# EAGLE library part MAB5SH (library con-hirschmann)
Female CONNECTOR 5 pins 90 deg. with shield, horizontal (DIN 41524)

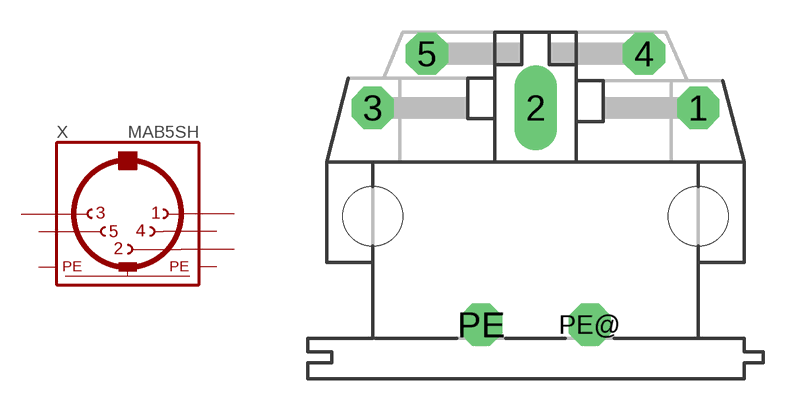
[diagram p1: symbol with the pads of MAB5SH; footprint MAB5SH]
Designator prefix X

## MAB5SH (OC_FARNELL: 809883; OC_NEWARK: unknown)  [MAB5SH]
1  1  pas
2  2  pas
3  3  pas
4  4  pas
5  5  pas
PE  PE  pwr
PE@  PE  pwr

## Footprint MAB5SH (pad centres in mm)
Female CONNECTOR 5 pins 90 deg. with shield, horizontal (DIN 41524)
drill 1.321 octagon: 1 7.62,5.08; 3 -7.62,5.08; 4 5.08,7.62; 5 -5.08,7.62; PE -2.54,-5.08; PE@ 2.54,-5.08
drill 1.321 long: 2 0,5.08
hole 2.794 at 7.62,0
hole 2.794 at -7.62,0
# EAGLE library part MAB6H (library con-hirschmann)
Female CONNECTOR 6 pins with shield, horizontal (DIN 45322)

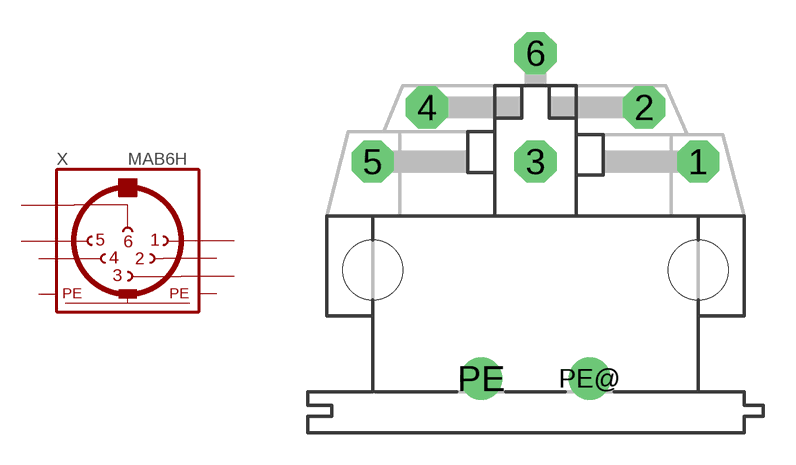
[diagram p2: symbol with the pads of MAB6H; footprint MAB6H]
Designator prefix X

## MAB6H (MF: FARNELL; MPN: MAB 6 H; OC_FARNELL: 809901; OC_NEWARK: 67C7887)  [MAB6H]
1  1  pas
2  2  pas
3  3  pas
4  4  pas
5  5  pas
6  6  pas
PE  PE  pwr
PE@  PE  pwr

## Footprint MAB6H (pad centres in mm)
Female CONNECTOR 6 pins with shield, horizontal (DIN 45322)
drill 1.321 octagon: 1 7.62,5.08; 2 5.08,7.62; 3 0,5.08; 4 -5.08,7.62; 5 -7.62,5.08; 6 0,10.16
drill 1.321 round: PE -2.54,-5.08; PE@ 2.54,-5.08
hole 2.794 at 7.62,0
hole 2.794 at -7.62,0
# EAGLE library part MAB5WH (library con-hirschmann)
Female CONNECTOR 5 pins with shield, horizontal (DIN 45327)

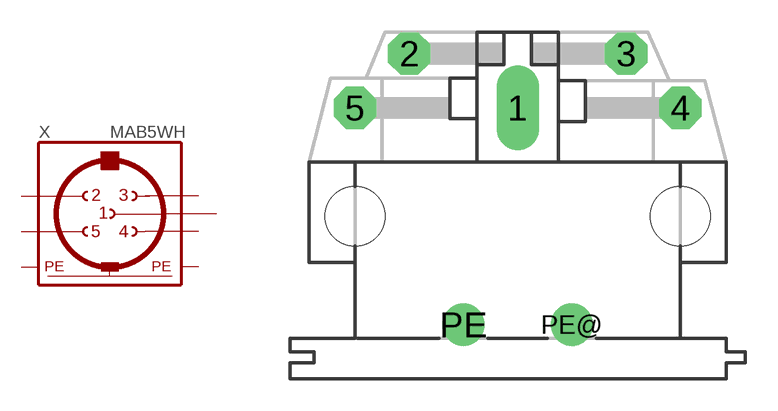
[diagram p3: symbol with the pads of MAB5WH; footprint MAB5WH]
Designator prefix X

## MAB5WH (OC_FARNELL: unknown; OC_NEWARK: unknown)  [MAB5WH]
1  1  pas
2  2  pas
3  3  pas
4  4  pas
5  5  pas
PE  PE  pwr
PE@  PE  pwr

## Footprint MAB5WH (pad centres in mm)
Female CONNECTOR 5 pins with shield, horizontal (DIN 45327)
drill 1.321 long: 1 0,5.08
drill 1.321 octagon: 2 -5.08,7.62; 3 5.08,7.62; 4 7.62,5.08; 5 -7.62,5.08
drill 1.321 round: PE -2.54,-5.08; PE@ 2.54,-5.08
hole 2.794 at 7.62,0
hole 2.794 at -7.62,0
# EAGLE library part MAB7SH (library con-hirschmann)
Female CONNECTOR 7 pins with shield, horizontal (DIN 45329)

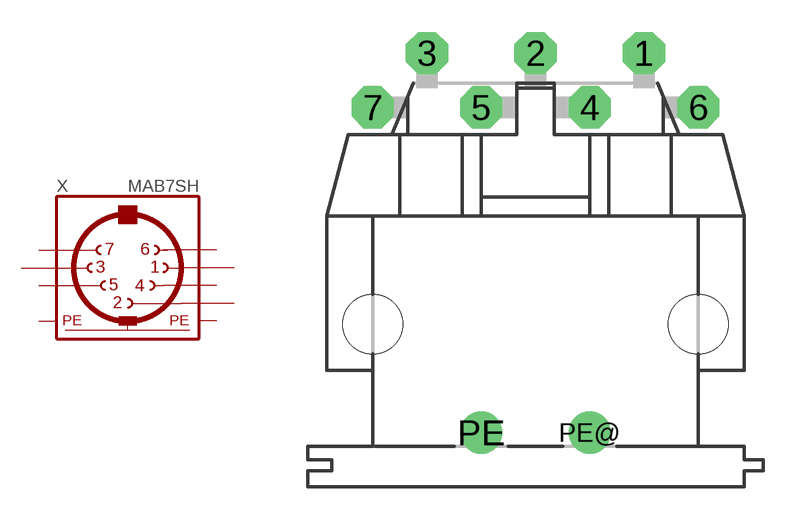
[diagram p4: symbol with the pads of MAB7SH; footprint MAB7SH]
Designator prefix X

## MAB7SH (OC_FARNELL: unknown; OC_NEWARK: unknown)  [MAB7SH]
1  1  pas
2  2  pas
3  3  pas
4  4  pas
5  5  pas
6  6  pas
7  7  pas
PE  PE  pwr
PE@  PE  pwr

## Footprint MAB7SH (pad centres in mm)
Female CONNECTOR 7 pins with shield, horizontal (DIN 45329)
drill 1.321 octagon: 1 5.08,12.7; 2 0,12.7; 3 -5.08,12.7; 4 2.54,10.16; 5 -2.54,10.16; 6 7.62,10.16; 7 -7.62,10.16
drill 1.321 round: PE -2.54,-5.08; PE@ 2.54,-5.08
hole 2.794 at 7.62,0
hole 2.794 at -7.62,0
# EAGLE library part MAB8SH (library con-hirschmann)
Female CONNECTOR 8 pins with shield, horizontal (DIN 41524)

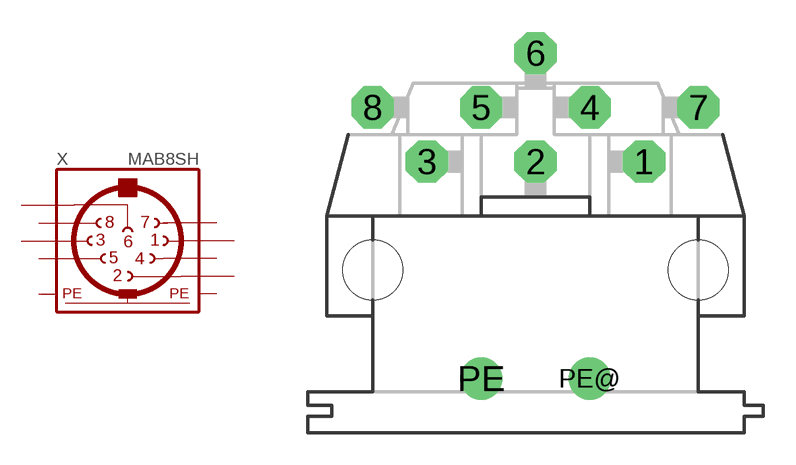
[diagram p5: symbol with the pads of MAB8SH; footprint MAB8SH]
Designator prefix X

## MAB8SH (MF: FARNELL; MPN: MAB 8 SH; OC_FARNELL: 809913; OC_NEWARK: 67C7888)  [MAB8SH]
1  1  pas
2  2  pas
3  3  pas
4  4  pas
5  5  pas
6  6  pas
7  7  pas
8  8  pas
PE  PE  pwr
PE@  PE  pwr

## Footprint MAB8SH (pad centres in mm)
Female CONNECTOR 8 pins with shield, horizontal (DIN 41524)
drill 1.321 octagon: 1 5.08,5.08; 2 0,5.08; 3 -5.08,5.08; 4 2.54,7.62; 5 -2.54,7.62; 6 0,10.16; 7 7.62,7.62; 8 -7.62,7.62
drill 1.321 round: PE -2.54,-5.08; PE@ 2.54,-5.08
hole 2.794 at -7.62,0
hole 2.794 at 7.62,0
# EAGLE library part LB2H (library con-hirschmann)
Female RF CONNECTOR horizontal

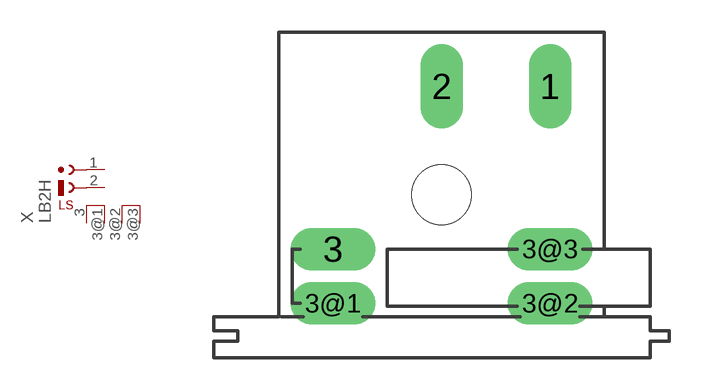
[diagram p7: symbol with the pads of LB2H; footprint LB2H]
Designator prefix X

## LB2H (OC_FARNELL: unknown; OC_NEWARK: unknown)  [LB2H]
1  1  pas
2  2  pas
3  3  pas
3@1  4  pas
3@2  5  pas
3@3  6  pas

## Footprint LB2H (pad centres in mm)
Female RF CONNECTOR horizontal
drill 1.321 long: 1 5.08,5.08; 2 0,5.08; 3 -5.08,-2.54; 3@1 -5.08,-5.08; 3@2 5.08,-5.08; 3@3 5.08,-2.54
hole 2.794 at 0,0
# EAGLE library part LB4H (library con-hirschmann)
Female RF CONNECTOR with 2 switches, horizontal

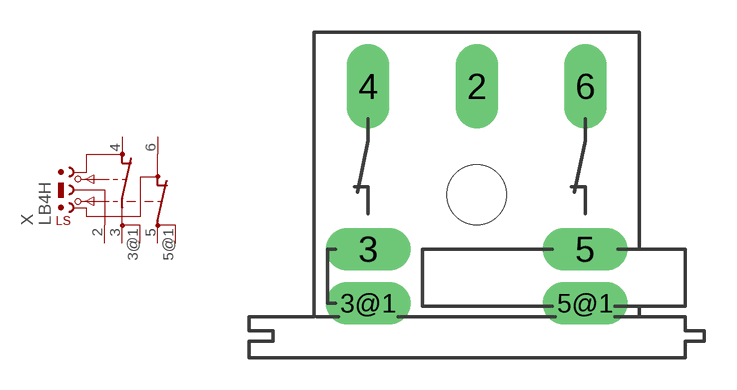
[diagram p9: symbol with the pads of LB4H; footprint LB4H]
Designator prefix X

## LB4H (OC_FARNELL: unknown; OC_NEWARK: unknown)  [LB4H]
2  2  pas
3  3  pas
3@1  3A  pas
4  4  pas
5  5  pas
5@1  5A  pas
6  6  pas

## Footprint LB4H (pad centres in mm)
Female RF CONNECTOR with 2 switches horizontal
drill 1.321 long: 2 0,5.08; 3 -5.08,-2.54; 3@1 -5.08,-5.08; 4 -5.08,5.08; 5 5.08,-2.54; 5@1 5.08,-5.08; 6 5.08,5.08
hole 2.794 at 0,0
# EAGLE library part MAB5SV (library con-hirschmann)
Female CONNECTOR 5 pins 90 deg. with shield, vertical (DIN41524)

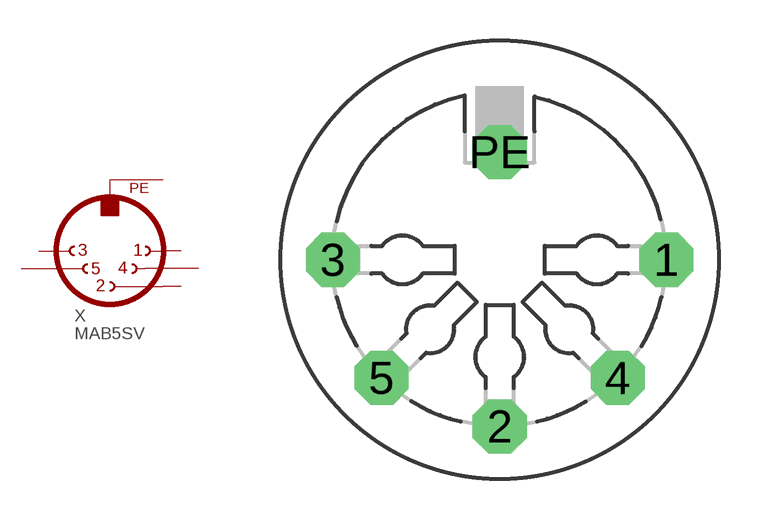
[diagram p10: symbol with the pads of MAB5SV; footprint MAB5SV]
Designator prefix X

## MAB5SV (OC_FARNELL: unknown; OC_NEWARK: unknown)  [MAB5SV]
1  1  pas
2  2  pas
3  3  pas
4  4  pas
5  5  pas
PE  PE  pwr

## Footprint MAB5SV (pad centres in mm)
Female CONNECTOR 5 pins 90 deg. with shield, vertical (DIN41524)
drill 1.321 octagon: 1 6.096,0; 2 0,-6.096; 3 -6.096,0; 4 4.318,-4.318; 5 -4.318,-4.318; PE 0,3.937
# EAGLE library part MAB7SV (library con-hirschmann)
Female CONNECTOR 7 pins 45 deg. with shield, vertical (DIN 45329)

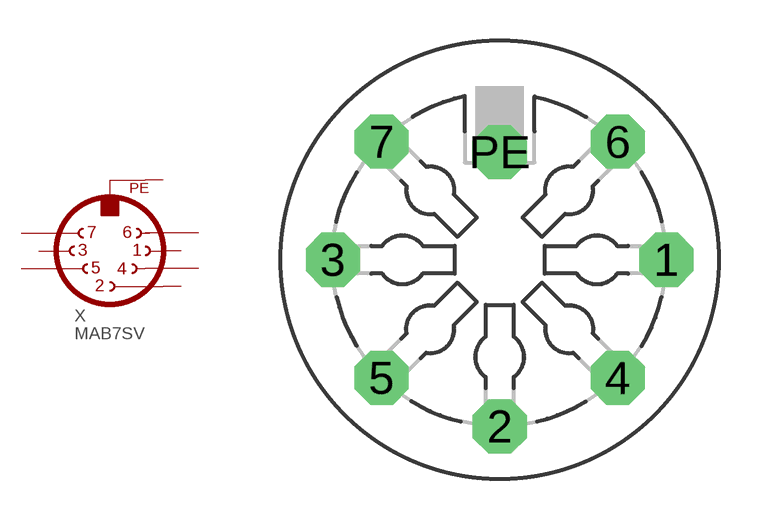
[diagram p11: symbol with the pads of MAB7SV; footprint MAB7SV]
Designator prefix X

## MAB7SV (OC_FARNELL: unknown; OC_NEWARK: unknown)  [MAB7SV]
1  1  pas
2  2  pas
3  3  pas
4  4  pas
5  5  pas
6  6  pas
7  7  pas
PE  PE  pwr

## Footprint MAB7SV (pad centres in mm)
Female CONNECTOR 7 pins 45 deg. with shield, vertical (DIN 45329)
drill 1.321 octagon: 1 6.096,0; 2 0,-6.096; 3 -6.096,0; 4 4.318,-4.318; 5 -4.318,-4.318; 6 4.318,4.318; 7 -4.318,4.318; PE 0,3.937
